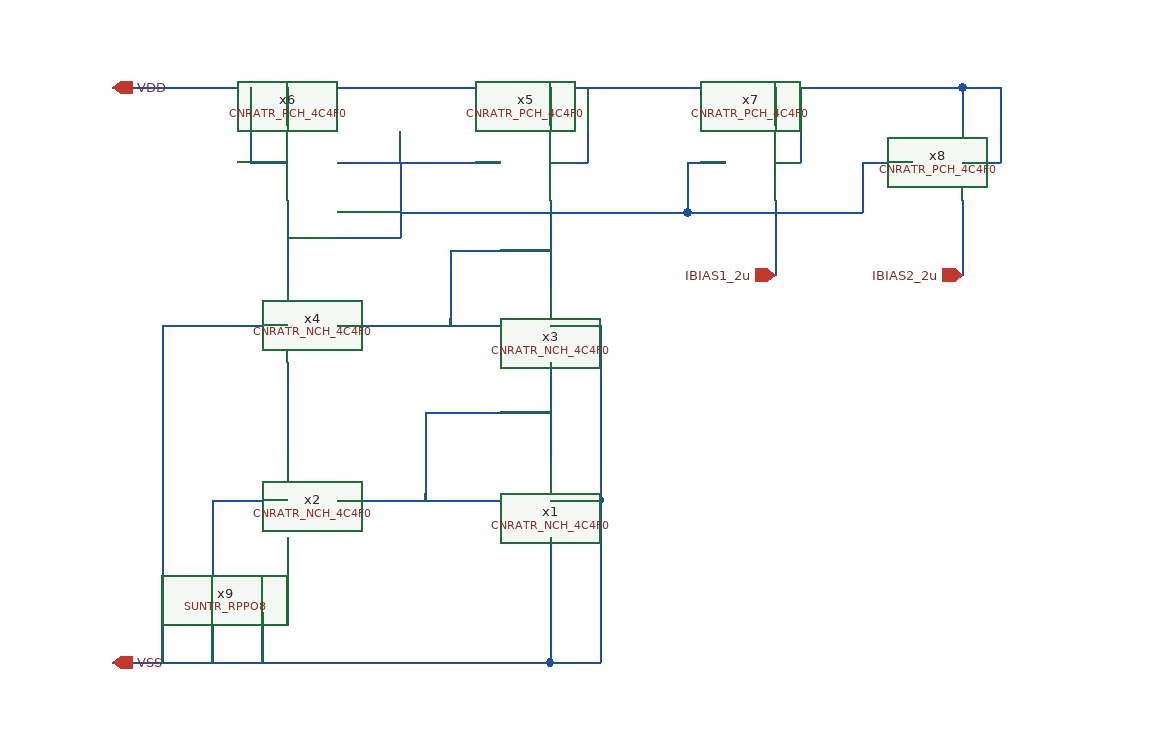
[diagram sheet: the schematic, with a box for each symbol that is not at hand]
v {xschem version=3.4.4 file_version=1.2
}
G {}
K {}
V {}
S {}
E {}
N 330 -190 330 -130 {
lab=IBIAS2_2u}
N 180 -190 180 -130 {
lab=IBIAS1_2u}
N -350 -280 330 -280 {
lab=VDD}
N 330 -280 330 -250 {
lab=VDD}
N 180 -280 180 -250 {
lab=VDD}
N -0 -280 -0 -250 {
lab=VDD}
N -210 -280 -210 -250 {
lab=VDD}
N -240 -220 -210 -220 {
lab=VDD}
N -240 -280 -240 -220 {
lab=VDD}
N -0 -220 30 -220 {
lab=VDD}
N 30 -280 30 -220 {
lab=VDD}
N 180 -220 200 -220 {
lab=VDD}
N 200 -280 200 -220 {
lab=VDD}
N 330 -220 360 -220 {
lab=VDD}
N 360 -280 360 -220 {
lab=VDD}
N 330 -280 360 -280 {
lab=VDD}
N -170 -220 -40 -220 {
lab=#net1}
N -210 -190 -210 -120 {
lab=#net1}
N -170 -90 -40 -90 {
lab=#net2}
N -0 -190 -0 -120 {
lab=#net2}
N -210 -60 -210 20 {
lab=#net3}
N -170 50 -40 50 {
lab=#net4}
N -0 -60 0 20 {
lab=#net4}
N -350 180 0 180 {
lab=VSS}
N 0 80 -0 120 {
lab=#net5}
N -100 -20 -0 -20 {
lab=#net4}
N -100 -20 -100 50 {
lab=#net4}
N -80 -150 -0 -150 {
lab=#net2}
N -80 -150 -80 -90 {
lab=#net2}
N -120 -220 -120 -160 {
lab=#net1}
N -210 -160 -120 -160 {
lab=#net1}
N -120 -180 110 -180 {
lab=#net1}
N 110 -220 110 -180 {
lab=#net1}
N 110 -220 140 -220 {
lab=#net1}
N 110 -180 250 -180 {
lab=#net1}
N 250 -220 250 -180 {
lab=#net1}
N 250 -220 290 -220 {
lab=#net1}
N -210 80 -210 100 {}
N -230 140 -230 180 {}
N -0 120 0 180 {}
N -310 -90 -210 -90 {}
N -310 -90 -310 180 {}
N -270 50 -210 50 {}
N -270 50 -270 180 {}
N -0 50 40 50 {}
N 40 50 40 180 {}
N 0 180 40 180 {}
N -0 -90 40 -90 {}
N 40 -90 40 50 {}
C {CNR_ATR_SKY130NM/CNR_ATR_SKY130NM/CNRATR_NCH_4C4F0.sym} -40 50 0 0 {name=x1 }
C {CNR_ATR_SKY130NM/CNR_ATR_SKY130NM/CNRATR_NCH_4C4F0.sym} -170 50 0 1 {name=x2 }
C {CNR_ATR_SKY130NM/CNR_ATR_SKY130NM/CNRATR_NCH_4C4F0.sym} -40 -90 0 0 {name=x3 }
C {CNR_ATR_SKY130NM/CNR_ATR_SKY130NM/CNRATR_NCH_4C4F0.sym} -170 -90 0 1 {name=x4 }
C {CNR_ATR_SKY130NM/CNR_ATR_SKY130NM/CNRATR_PCH_4C4F0.sym} -40 -220 0 0 {name=x5 }
C {CNR_ATR_SKY130NM/CNR_ATR_SKY130NM/CNRATR_PCH_4C4F0.sym} -170 -220 0 1 {name=x6 }
C {CNR_ATR_SKY130NM/CNR_ATR_SKY130NM/CNRATR_PCH_4C4F0.sym} 140 -220 0 0 {name=x7 }
C {devices/iopin.sym} -350 -280 0 1 {name=p1 lab=VDD}
C {devices/iopin.sym} -350 180 0 1 {name=p2 lab=VSS}
C {devices/iopin.sym} 180 -130 1 0 {name=p3 lab=IBIAS1_2u}
C {devices/iopin.sym} 330 -130 1 0 {name=p4 lab=IBIAS2_2u}
C {CNR_ATR_SKY130NM/CNR_ATR_SKY130NM/CNRATR_PCH_4C4F0.sym} 290 -220 0 0 {name=x8 }
C {SUN_TR_SKY130NM/SUNTR_RPPO8.sym} -210 100 1 0 {name=x9 }
